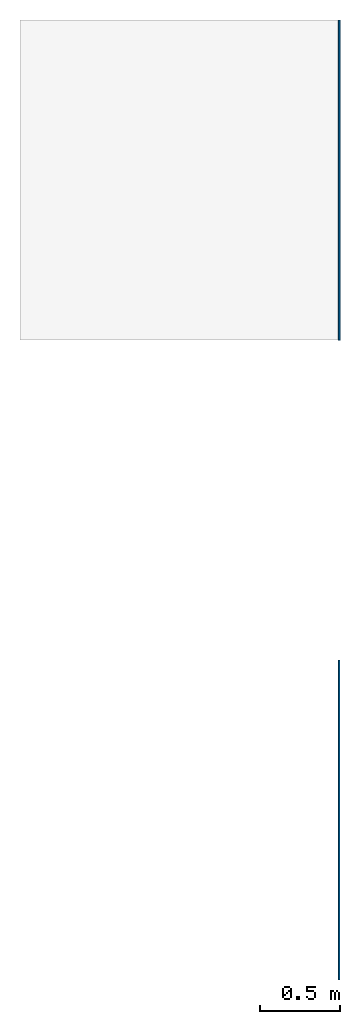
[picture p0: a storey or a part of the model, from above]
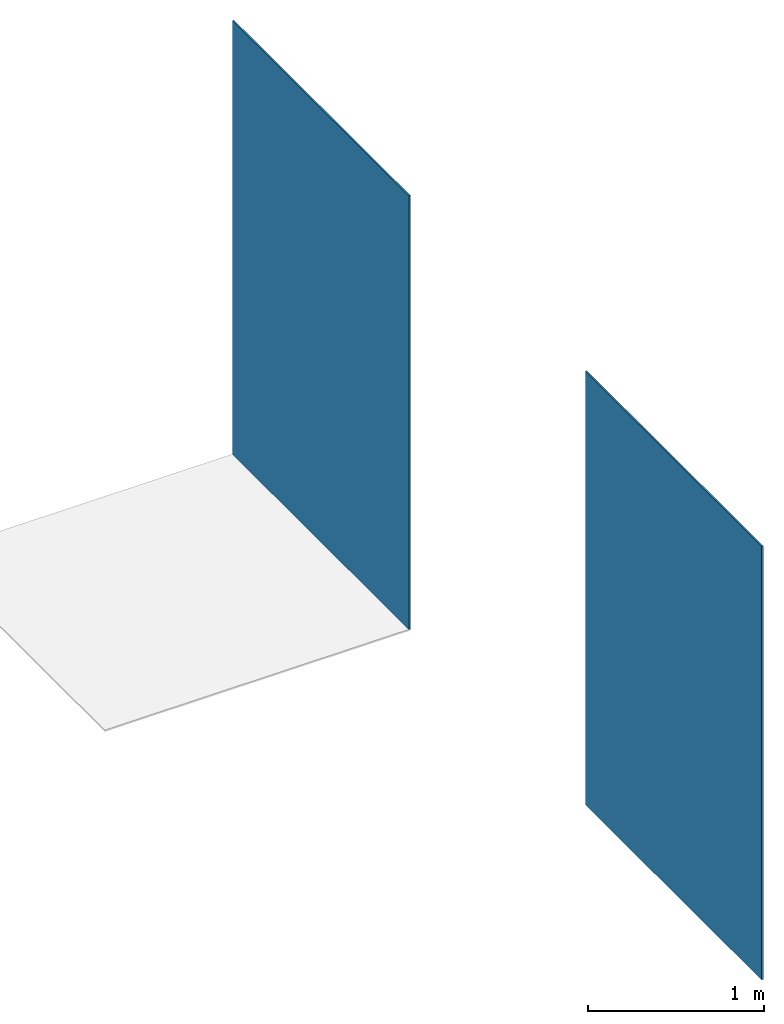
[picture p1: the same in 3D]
Properties of the parts of a building model (IFC2X3)

# File
Description: ViewDefinition [CoordinationView_V2.0]
File name: Project Number
Time: 2018-07-16T11:43:41
Written by: The EXPRESS Data Manager Version 5.02.0100.07 : 28 Aug 2013
Made in: 20171027_0315(x64) - Exporter 17.2.0.0 - Alternate UI 17.2.0.0
Comment: STEP Physical File produced by: The EXPRESS Data Manager Version 5.02.0100.07 : 28 Aug 2013 * Module: EDMstepFileFactory/EDMstandAlone * Creation date: Mon Jul 16 11:43:41 2018 * Host: aieadsegarra * Database: C:\Users\ES0050~3\AppData\Local\Temp\{0396895E-070C-49F2-8FFB-B762DF7B74EE}\ifc * Database version: 5507 * Database creation date: Mon Jul 16 11:43:41 2018 * Schema: IFC2X3 * Model: DataRepository.ifc * Model creation date: Mon Jul 16 11:43:41 2018 * Header model: DataRepository.ifc_HeaderModel * Header model creation date: Mon Jul 16 11:43:41 2018 * EDMuser: sdai-user * EDMgroup: sdai-group * License ID and type: 5605 : Permanent license. Expiry date: * EDMstepFileFactory options: 020000

# IfcProject, Project Number
LongName: Project Name; Phase: Project Status

# IfcSite, Default
RefLatitude: 42, 21, 31, 181945; RefLongitude: -71, -3, -24, -263305; RefElevation: 0 mm

# IfcBuildingStorey, Level 1
LongName: Level 1; Elevation: 0 mm

# IfcCovering: Floor:PGR_Porcelanosa_CeramicTiles_Travertino_Medici-596x596mm-100191337, Floor:PGR_Porcelanosa_CeramicTiles_Travertino_Medici-596x596mm-100191337:211428
In: Level 1
PredefinedType: FLOORING; Material: PGR_Porcelanosa_CeramicTiles_Travertino_Medici-596x596mm-100191337 10.3 mm
NBS_General - Author: Porcelanosa Group; BIMObjectName: PGR_Porcelanosa_CeramicTiles_Travertino_Medici-596x596mm-100191337; ManufacturerURL: www.porcelanosa.com; NBSDescription: Ceramic Tiles; NBSReference: 45-80-95/310; ProductInformation: http://calidad.info-grupo.com:8081/GeneraFicha3/PDF?articulo=100191337&lang=EN&un=0; Revision: n/a; Uniclass2015Code: Pr_35_93_96_19; Uniclass2015Title: Ceramic Tiles; Uniclass2015Version: Products v1.5; Version: 1
COBie - AccessibilityPerformance: See ProductInformation (Technical PDF); AssetType: Fixed; Category: Floors; CodePerformance: ISO-13006:2012; UNE-EN 14411:2012; Color: Beige; Constituents: Clays, feldespat and glaze; Description: TRAVERTINO series from PORCELANOSA, BEIGE color and GLOSS finish, 59.6x59.6 cm (10.5 mm thickness), group BIa, according to UNE-EN 14411, water absortion capacity E<=0.5%, flexural strength >40 N/mm² and breaking strength with an average value of 3310 N (Min. 1300 N); DurationUnit: year; ExpectedLife: 50; Features: See ProductInformation (Technical PDF); Grade: First quality; Manufacturer: bim.gp@porcelanosagrupo.com; ModelNumber: 100191337; ModelReference: Travertino Medici 59.6x59.6 cm; Name: CeramicTiles_Travertino_Medici-596x596mm-100191337; NominalHeight: 10.5 mm; NominalLength: 596 mm; NominalWidth: 596 mm; ReplacementCost: n/a; Shape: Squared; Size: 596x596x10.5 mm; Sustainability Performance: See ProductInformation (Technical PDF); WarrantyDescription: Manufacturer warranty, applicable worldwide, with the pertinent national legislation prevailing in all cases and covering at least a 3-year period; all products must have been manufactured and fitted in accordance with the Fabricator's Manual, and have been used and cared for in accordance with the Guide to Use, Cleaning and Care available on the web page www.porcelanosa.com; WarrantyDurationLabor: n/a; WarrantyDurationParts: 3; WarrantyDurationUnit: year; WarrantyGuarantorLabor: n/a; WarrantyGuarantorParts: bim.gp@porcelanosagrupo.com; AssetIdentifier: n/a; BarCode: n/a; InstallationDate: 1900-12-31T23:59:59; TagNumber: n/a; WarrantyStartDate: 1900-12-31T23:59:59
Pset_CoveringCommon - Reference: n/a; AcousticRating: n/a; Finish: Tone Variations, Gloss, Marble, Rectified; FireRating: A1; FlammabilityRating: Class 0; FragilityRating: n/a; IsExternal: yes; Material: Ceramic; SurfaceSpreadOfFlame: Class 0; ThermalTransmittance: 219.048 kg/K/s3; TotalThickness: 10.5 mm
Pset_CoveringFlooring - HasAntiStaticSurface: no; HasNonSkidSurface: no
IFC - IfcExportType: FLOORING; IfcExportAS: IfcCovering
NBS_Data - HasSurfaceRoughness: no; AbrasionResistance: 3: Light-Without External Access; BreakingStrength: Average Value: 3310 N (Min. 1300 N); ChemicalResistance: Class 'A' for swimming pools and cleaning products (resists attack); minimum Class 'B' for acids and bases; Collection: Gres; CreationDate: 2018/07; Dcof: n/a; FlexuralStrength: http://www.porcelanosa.com/product_finder/resources/pdf/inscol/files/GENCER-Fixing-Instructions.pdf; FrostResistance: >40 N/mm²; Group: Conforms to ISO 10545-9; MoistureExpansion: <(6.5x10e-6)/°K; RampTest: <0.1 mm/m; RecycledContent: n/a; Series: >6.5%; SlipResistanceValuePendulumTestValue: Travertino; StainResistance: n/a; SurfaceQuality: Class 5: Easy cleaning with water; ThermalShockResistance: Without surface defects; UpecC: n/a; UpecE: n/a; UpecP: n/a; UpecU: Conforms to ISO 10545–12; WaterAbsorption: n/a

# IfcWallStandardCase: Basic Wall:PGR_Porcelanosa_CeramicTiles_Travertino_Medici-450x1200mm-100190496, Basic Wall:PGR_Porcelanosa_CeramicTiles_Travertino_Medici-450x1200mm-100190496:211301
In: Level 1
Type - PredefinedType: STANDARD; Material: PGR_Porcelanosa_CeramicTiles_Travertino_Medici-450x1200mm-100190496 10.3 mm
Type - NBS_General - Author: Porcelanosa Group; BIMObjectName: PGR_Porcelanosa_CeramicTiles_Travertino_Medici-450x1200mm-100190496; ManufacturerURL: www.porcelanosa.com; NBSDescription: Ceramic Tiles; NBSReference: 45-80-95/310; ProductInformation: http://calidad.info-grupo.com:8081/GeneraFicha3/PDF?articulo=100190496&lang=EN&un=0; Revision: n/a; Uniclass2015Code: Pr_35_93_96_19; Uniclass2015Title: Ceramic Tiles; Uniclass2015Version: Products v1.5; Version: 1
Type - COBie - AccessibilityPerformance: See ProductInformation (Technical PDF); AssetType: Fixed; Category: Walls; CodePerformance: ISO-13006:2012; UNE-EN 14411:2012; Color: Beige; Constituents: Clays, feldespat and glaze; Description: Rectified Monoporous, TRAVERTINO series from PORCELANOSA, BEIGE color and GLOSS finish, 45x120 cm (10.3 mm thickness), group BIII, according to UNE-EN 14411, water absortion capacity 10%<=E<=20%, flexural strength >23 N/mm² and breaking strength with an average value of 1337 N (Min. 600 N); DurationUnit: year; ExpectedLife: 50; Features: See ProductInformation (Technical PDF); Grade: First quality; Manufacturer: bim.gp@porcelanosagrupo.com; ModelNumber: 100190496; ModelReference: Travertino Medici 45x120 cm; Name: CeramicTiles_Travertino_Medici-450x1200mm-100190496; NominalHeight: 10.3 mm; NominalLength: 1200 mm; NominalWidth: 450 mm; ReplacementCost: n/a; Shape: Rectangular; Size: 450x1200x10.3 mm; Sustainability Performance: See ProductInformation (Technical PDF); WarrantyDescription: Manufacturer warranty, applicable worldwide, with the pertinent national legislation prevailing in all cases and covering at least a 3-year period; all products must have been manufactured and fitted in accordance with the Fabricator's Manual, and have been used and cared for in accordance with the Guide to Use, Cleaning and Care available on the web page www.porcelanosa.com; WarrantyDurationLabor: n/a; WarrantyDurationParts: 3; WarrantyDurationUnit: year; WarrantyGuarantorLabor: n/a; WarrantyGuarantorParts: bim.gp@porcelanosagrupo.com
Type - Pset_CoveringCommon - AcousticRating: n/a; Finish: Tone Variations, Gloss, Marble, Rectified; FireRating: A1; FlammabilityRating: Class 0; FragilityRating: n/a; IsExternal: no; Material: Ceramic; SurfaceSpreadOfFlame: Class 0; ThermalTransmittance: 223.301 kg/K/s3; TotalThickness: 10.3 mm; Reference: n/a
Type - IFC - IfcExportType: CLADDING; IfcExportAS: IfcCovering
Type - NBS_Data - AbrasionResistance: 1: Wall Tiles; BreakingStrength: Average Value: 1337 N (Min. 600 N); ChemicalResistance: Class 'A' for swimming pools and cleaning products (resists attack); minimum Class 'B' for acids and bases; Collection: Revestimiento Ceramico Rectificado; CreationDate: 2018/07; Dcof: n/a; FlexuralStrength: >23 N/mm²; FrostResistance: n/a; Group: BIII; HasSurfaceRoughness: no; MoistureExpansion: <0.1 mm/m; RampTest: n/a; RecycledContent: >18%; Series: Travertino; SlipResistanceValuePendulumTestValue: n/a; StainResistance: Class 5: Easy cleaning with water; SurfaceQuality: Without surface defects; ThermalShockResistance: Conforms to ISO 10545–12; UpecC: n/a; UpecE: n/a; UpecP: n/a; UpecU: n/a; WaterAbsorption: 10%<=E<=20%
COBie - AssetIdentifier: n/a; BarCode: n/a; InstallationDate: 1900-12-31T23:59:59; TagNumber: n/a; WarrantyStartDate: 1900-12-31T23:59:59

# IfcWallStandardCase: Basic Wall:PGR_Porcelanosa_CeramicTiles_Travertino_Medici-596x596mm-100191337, Basic Wall:PGR_Porcelanosa_CeramicTiles_Travertino_Medici-596x596mm-100191337:211433
In: Level 1
Type - PredefinedType: STANDARD; Material: PGR_Porcelanosa_CeramicTiles_Travertino_Medici-596x596mm-100191337 10.3 mm
Type - NBS_General - Author: Porcelanosa Group; BIMObjectName: PGR_Porcelanosa_CeramicTiles_Travertino_Medici-596x596mm-100191337; ManufacturerURL: www.porcelanosa.com; NBSDescription: Ceramic Tiles; NBSReference: 45-80-95/310; ProductInformation: http://calidad.info-grupo.com:8081/GeneraFicha3/PDF?articulo=100191337&lang=EN&un=0; Revision: n/a; Uniclass2015Code: Pr_35_93_96_19; Uniclass2015Title: Ceramic Tiles; Uniclass2015Version: Products v1.5; Version: 1
Type - COBie - AccessibilityPerformance: See ProductInformation (Technical PDF); AssetType: Fixed; Category: Walls; CodePerformance: ISO-13006:2012; UNE-EN 14411:2012; Color: Beige; Constituents: Clays, feldespat and glaze; Description: TRAVERTINO series from PORCELANOSA, BEIGE color and GLOSS finish, 59.6x59.6 cm (10.5 mm thickness), group BIa, according to UNE-EN 14411, water absortion capacity E<=0.5%, flexural strength >40 N/mm² and breaking strength with an average value of 3310 N (Min. 1300 N); DurationUnit: year; ExpectedLife: 50; Features: See ProductInformation (Technical PDF); Grade: First quality; Manufacturer: bim.gp@porcelanosagrupo.com; ModelNumber: 100191337; ModelReference: Travertino Medici 59.6x59.6 cm; Name: CeramicTiles_Travertino_Medici-596x596mm-100191337; NominalHeight: 10.5 mm; NominalLength: 596 mm; NominalWidth: 596 mm; ReplacementCost: n/a; Shape: Squared; Size: 596x596x10.5 mm; Sustainability Performance: See ProductInformation (Technical PDF); WarrantyDescription: Manufacturer warranty, applicable worldwide, with the pertinent national legislation prevailing in all cases and covering at least a 3-year period; all products must have been manufactured and fitted in accordance with the Fabricator's Manual, and have been used and cared for in accordance with the Guide to Use, Cleaning and Care available on the web page www.porcelanosa.com; WarrantyDurationLabor: n/a; WarrantyDurationParts: 3; WarrantyDurationUnit: year; WarrantyGuarantorLabor: n/a; WarrantyGuarantorParts: bim.gp@porcelanosagrupo.com
Type - Pset_CoveringCommon - Reference: n/a; IsExternal: yes; AcousticRating: n/a; Finish: Tone Variations, Gloss, Marble, Rectified; FireRating: A1; FlammabilityRating: Class 0; FragilityRating: n/a; Material: Ceramic; SurfaceSpreadOfFlame: Class 0; ThermalTransmittance: 219.048 kg/K/s3; TotalThickness: 10.5 mm
Type - IFC - IfcExportType: FLOORING; IfcExportAS: IfcCovering
Type - NBS_Data - HasSurfaceRoughness: no; AbrasionResistance: 3: Light-Without External Access; BreakingStrength: Average Value: 3310 N (Min. 1300 N); ChemicalResistance: Class 'A' for swimming pools and cleaning products (resists attack); minimum Class 'B' for acids and bases; Collection: Gres; CreationDate: 2018/07; Dcof: n/a; FlexuralStrength: >40 N/mm²; FrostResistance: Conforms to ISO 10545-9; Group: BIa; MoistureExpansion: <0.1 mm/m; RampTest: n/a; RecycledContent: >6.5%; Series: Travertino; SlipResistanceValuePendulumTestValue: n/a; StainResistance: Class 5: Easy cleaning with water; SurfaceQuality: Without surface defects; ThermalShockResistance: Conforms to ISO 10545–12; UpecC: n/a; UpecE: n/a; UpecP: n/a; UpecU: n/a; WaterAbsorption: E<=0.5%
COBie - AssetIdentifier: n/a; BarCode: n/a; InstallationDate: 1900-12-31T23:59:59; TagNumber: n/a; WarrantyStartDate: 1900-12-31T23:59:59
